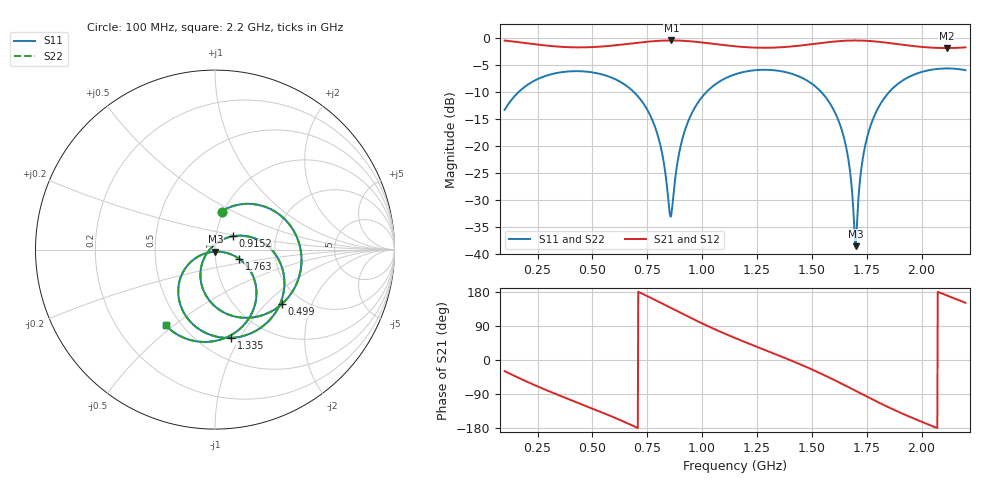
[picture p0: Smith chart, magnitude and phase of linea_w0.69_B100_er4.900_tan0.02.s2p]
! Chirptenna · simulación 3D de una microstrip de dos puertos (S12 = S21, S22 = S11 por simetría)
# HZ S RI R 50
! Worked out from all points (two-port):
!   1101 points, 100 MHz to 2.2 GHz, reference 50 ohm
!   highest |S21| = -0.45 dB at 859.8 MHz (marker M1); lowest = -1.9 dB at 2.114 GHz (marker M2)
!   |S21| within 3 dB of the highest: start of sweep to end of sweep
!   lowest |S11| = -38.6 dB at 1.7 GHz (marker M3), VSWR 1.02, Z = 50.2 - j1.16 ohm
!   |S11| at or under -10 dB: start of sweep to 164.4 MHz; 688.3 MHz to 1.021 GHz (332.2 MHz wide, 38.9 % of centre); 1.543 GHz to 1.853 GHz (310.5 MHz wide, 18.3 % of centre)
!   |S22| runs from -38.6 to -5.6 dB; largest |S21 - S12| = 0
!   S11 on the Smith chart (normalised r, x): 100 MHz: 0.98, +0.44; 499 MHz: 1.59, -1.25; 915.2 MHz: 1.21, +0.18; 1.335 GHz: 0.70, -0.92; 1.763 GHz: 1.30, -0.13; 2.2 GHz: 0.41, -0.47
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1e8  0.0365 0.2123  0.8259 -0.4649  0.8259 -0.4649  0.0365 0.2123
2.584545e8  0.3869 0.1708  0.2718 -0.8219  0.2718 -0.8219  0.3869 0.1708
4.512727e8  0.4375 -0.2239  -0.3713 -0.7302  -0.3713 -0.7302  0.4375 -0.2239
4.99e8  0.3728 -0.303  -0.5064 -0.65  -0.5064 -0.65  0.3728 -0.303
6.899091e8  -0.00294 -0.3139  -0.8929 -0.0797  -0.8929 -0.0797  -0.00294 -0.3139
8.006364e8  -0.076 -0.0925  -0.848 0.4098  -0.848 0.4098  -0.076 -0.0925
8.598182e8  -0.0101 0.0207  -0.6933 0.649  -0.6933 0.649  -0.0101 0.0207
8.884545e8  0.0435 0.0566  -0.5896 0.742  -0.5896 0.742  0.0435 0.0566
9.151818e8  0.1011 0.0747  -0.4806 0.8109  -0.4806 0.8109  0.1011 0.0747
1.004909e9  0.2908 0.0228  -0.0831 0.9036  -0.0831 0.9036  0.2908 0.0228
1.15e9  0.3755 -0.2663  0.4431 0.7116  0.4431 0.7116  0.3755 -0.2663
1.335182e9  0.0916 -0.4921  0.7878 0.2136  0.7878 0.2136  0.0916 -0.4921
1.501273e9  -0.1859 -0.3262  0.7945 -0.3728  0.7945 -0.3728  -0.1859 -0.3262
1.636818e9  -0.1257 -0.0607  0.4306 -0.8356  0.4306 -0.8356  -0.1257 -0.0607
1.669273e9  -0.0642 -0.0249  0.288 -0.9024  0.288 -0.9024  -0.0642 -0.0249
1.699818e9  0.00176 -0.0116  0.1422 -0.9387  0.1422 -0.9387  0.00176 -0.0116
1.728455e9  0.0647 -0.0185  0.00154 -0.9471  0.00154 -0.9471  0.0647 -0.0185
1.762818e9  0.1336 -0.0505  -0.1638 -0.9247  -0.1638 -0.9247  0.1336 -0.0505
1.850636e9  0.2292 -0.2119  -0.5157 -0.7377  -0.5157 -0.7377  0.2292 -0.2119
1.970909e9  0.1401 -0.4403  -0.7656 -0.3427  -0.7656 -0.3427  0.1401 -0.4403
2.114091e9  -0.1299 -0.5058  -0.7967 0.1304  -0.7967 0.1304  -0.1299 -0.5058
2.2e9  -0.275 -0.4214  -0.7159 0.3983  -0.7159 0.3983  -0.275 -0.4214
